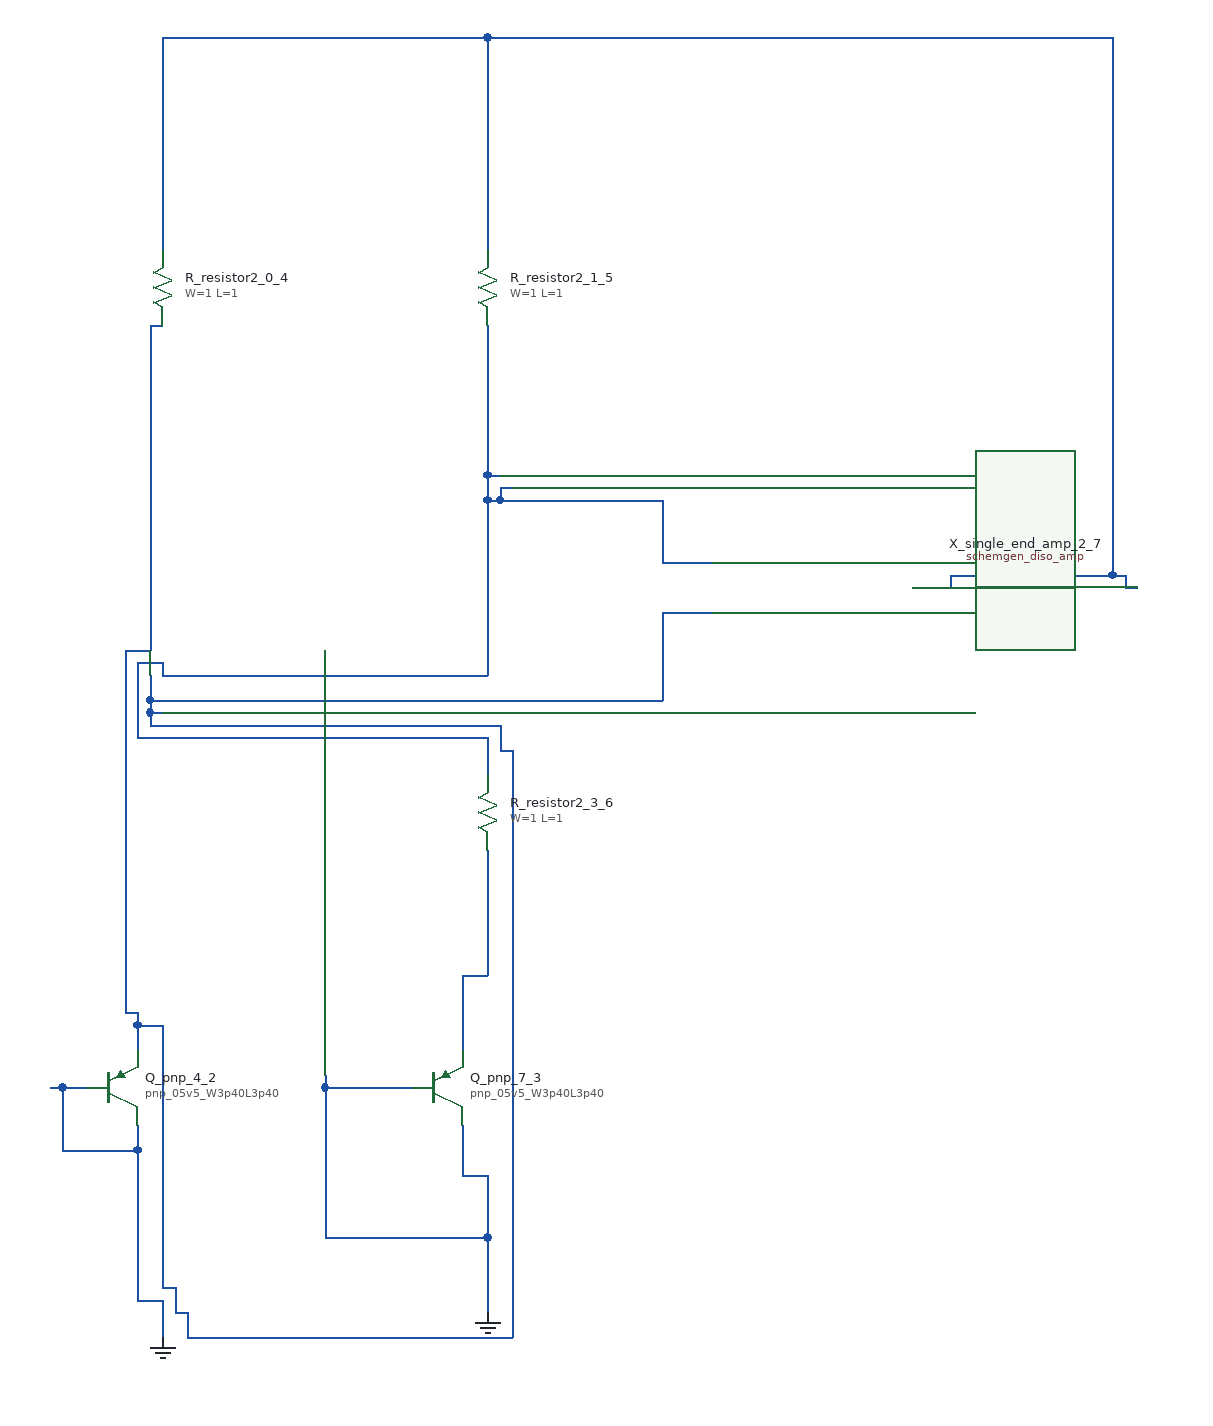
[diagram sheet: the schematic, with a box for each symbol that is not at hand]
v {xschem version=3.4.8 file_version=1.2}
G {}
K {}
V {}
S {}
E {}
C {devices/gnd.sym} 200 1060 0 0 {name="l_gnd_5_0" lab="GND"}
C {devices/gnd.sym} 460 1040 0 0 {name="l_gnd_6_1" lab="GND"}
C {sky130_fd_pr/pnp_05v5.sym} 160 860 0 0 {name="Q_pnp_4_2"
model=pnp_05v5_W3p40L3p40
m=1
spiceprefix=X
}
C {sky130_fd_pr/pnp_05v5.sym} 420 860 0 0 {name="Q_pnp_7_3"
model=pnp_05v5_W3p40L3p40
m=1
spiceprefix=X
}
C {sky130_fd_pr/res_generic_po.sym} 200 220 2 0 {name="R_resistor2_0_4"
W=1
L=1
model=res_generic_po
spiceprefix=X
mult=1}
C {sky130_fd_pr/res_generic_po.sym} 460 220 2 0 {name="R_resistor2_1_5"
W=1
L=1
model=res_generic_po
spiceprefix=X
mult=1}
C {sky130_fd_pr/res_generic_po.sym} 460 640 2 0 {name="R_resistor2_3_6"
W=1
L=1
model=res_generic_po
spiceprefix=X
mult=1}
C {schemgen_diso_amp.sym} 720 460 2 1 {name="X_single_end_amp_2_7"}
N 180 1030 200 1030 {}
N 330 980 460 980 {}
N 440 930 460 930 {}
N 120 910 180 910 {}
N 110 860 120 860 {}
N 120 860 140 860 {}
N 330 860 400 860 {}
N 120 910 120 860 {}
N 180 1030 180 910 {}
N 180 910 180 890 {}
N 200 1060 200 1030 {}
N 330 980 330 860 {}
N 330 860 330 850 {}
N 440 930 440 890 {}
N 460 1040 460 980 {}
N 460 980 460 930 {}
N 800 460 830 460 {}
N 970 460 980 460 {}
N 830 450 960 450 {}
N 960 450 970 450 {}
N 200 20 460 20 {}
N 460 20 960 20 {}
N 200 190 200 20 {}
N 460 190 460 20 {}
N 830 460 830 450 {}
N 960 450 960 20 {}
N 970 460 970 450 {}
N 180 580 460 580 {}
N 200 530 460 530 {}
N 180 520 200 520 {}
N 600 440 640 440 {}
N 460 390 470 390 {}
N 470 390 600 390 {}
N 470 380 480 380 {}
N 460 370 470 370 {}
N 180 580 180 520 {}
N 200 530 200 520 {}
N 460 610 460 580 {}
N 460 530 460 390 {}
N 460 390 460 370 {}
N 460 370 460 250 {}
N 470 390 470 380 {}
N 600 440 600 390 {}
N 440 770 460 770 {}
N 440 830 440 770 {}
N 460 770 460 670 {}
N 220 1060 480 1060 {}
N 210 1040 220 1040 {}
N 200 1020 210 1020 {}
N 180 810 200 810 {}
N 170 800 180 800 {}
N 470 590 480 590 {}
N 190 570 470 570 {}
N 190 560 200 560 {}
N 190 550 600 550 {}
N 170 510 190 510 {}
N 600 480 640 480 {}
N 190 250 200 250 {}
N 170 800 170 510 {}
N 180 830 180 810 {}
N 180 810 180 800 {}
N 190 570 190 560 {}
N 190 560 190 550 {}
N 190 550 190 530 {}
N 190 510 190 250 {}
N 200 1020 200 810 {}
N 210 1040 210 1020 {}
N 220 1060 220 1040 {}
N 470 590 470 570 {}
N 480 1060 480 590 {}
N 600 550 600 480 {}
